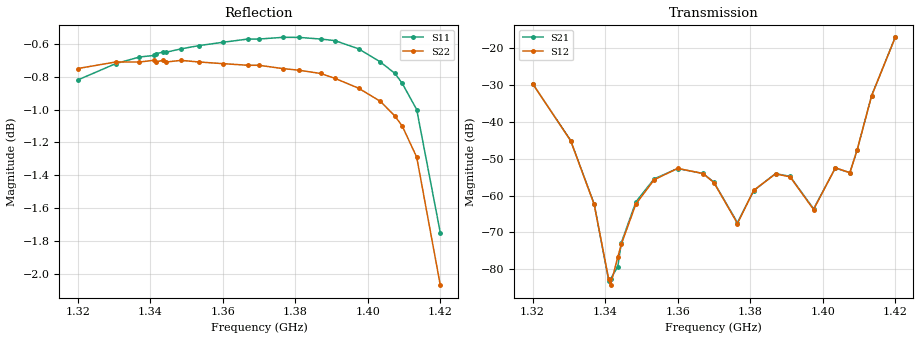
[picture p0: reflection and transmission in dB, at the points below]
!Agilent Technologies,E8363B,SG43030131,A.07.50.48
!Agilent E8363B: A.07.50.48
!Date: Friday, November 21, 2025 21:12:36
!Correction: S11(Full 2 Port(1,2))
!S21(Full 2 Port(1,2))
!S12(Full 2 Port(1,2))
!S22(Full 2 Port(1,2))
!S2P File: Measurements: S11, S21, S12, S22:
# Hz S  dB  R 50
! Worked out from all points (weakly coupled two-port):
!   201 points, 1.32 GHz to 1.42 GHz, reference 50 ohm
!   highest |S21| = -17.16 dB at 1.42 GHz (marker M1); lowest = -83.0 dB at 1.341 GHz (marker M2)
!   lowest |S11| = -1.8 dB at 1.42 GHz (marker M3), VSWR 9.94, Z = 33.1 - j114 ohm
!   |S11| at or under -10 dB: nowhere
!   |S22| runs from -2.1 to -0.7 dB; largest |S21 - S12| = 0.00018
!   S11 on the Smith chart (normalised r, x): 1.32 GHz: 0.05, +0.06; 1.341 GHz: 0.05, +0.47; 1.367 GHz: 0.07, +1.07; 1.391 GHz: 0.24, +2.47; 1.409 GHz: 21, -2; 1.42 GHz: 0.66, -2.28
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1.32e9  -0.82 172.6  -29.66 -57.0  -29.66 -57.1  -0.75 -132.4
1.3305e9  -0.72 149.9  -45.09 -71.3  -45.10 -71.3  -0.71 -154.3
1.337e9  -0.68 137.4  -62.31 -59.2  -62.41 -60.9  -0.71 -167.3
1.341e9  -0.67 130.1  -83.03 27.6  -82.65 41.1  -0.70 -175.2
1.3415e9  -0.66 129.2  -82.62 54.3  -84.26 72.1  -0.71 -176.2
1.3435e9  -0.65 125.6  -79.26 167.2  -76.67 159.6  -0.70 179.9
1.3445e9  -0.65 123.8  -72.73 -170.9  -73.10 -176.1  -0.71 177.9
1.3485e9  -0.63 116.8  -61.72 -148.1  -62.28 -146.4  -0.70 170.1
1.3535e9  -0.61 108.4  -55.49 -143.7  -55.74 -143.7  -0.71 160.3
1.36e9  -0.59 97.5  -52.68 -147.8  -52.64 -148.2  -0.72 147.3
1.367e9  -0.57 85.9  -54.02 -153.2  -54.03 -153.8  -0.73 133.0
1.37e9  -0.57 81.0  -56.38 -153.3  -56.47 -152.9  -0.73 126.7
1.3765e9  -0.56 70.0  -67.32 -83.6  -67.57 -82.1  -0.75 112.6
1.381e9  -0.56 62.3  -58.66 -25.4  -58.56 -24.6  -0.76 102.4
1.387e9  -0.57 51.5  -54.05 -22.6  -54.13 -23.0  -0.78 87.9
1.391e9  -0.58 43.8  -54.81 -22.0  -54.92 -24.0  -0.81 77.6
1.3975e9  -0.63 30.4  -63.59 54.0  -63.79 52.0  -0.87 59.2
1.4035e9  -0.71 16.3  -52.55 112.0  -52.46 111.9  -0.95 39.9
1.4075e9  -0.78 5.5  -53.81 159.4  -53.82 159.4  -1.04 25.1
1.4095e9  -0.84 -0.4  -47.67 -145.9  -47.67 -145.4  -1.10 17.0
1.4135e9  -1.00 -14.1  -32.94 -130.9  -32.95 -131.0  -1.29 -1.4
1.42e9  -1.75 -44.5  -17.16 -158.2  -17.17 -158.2  -2.07 -40.6
